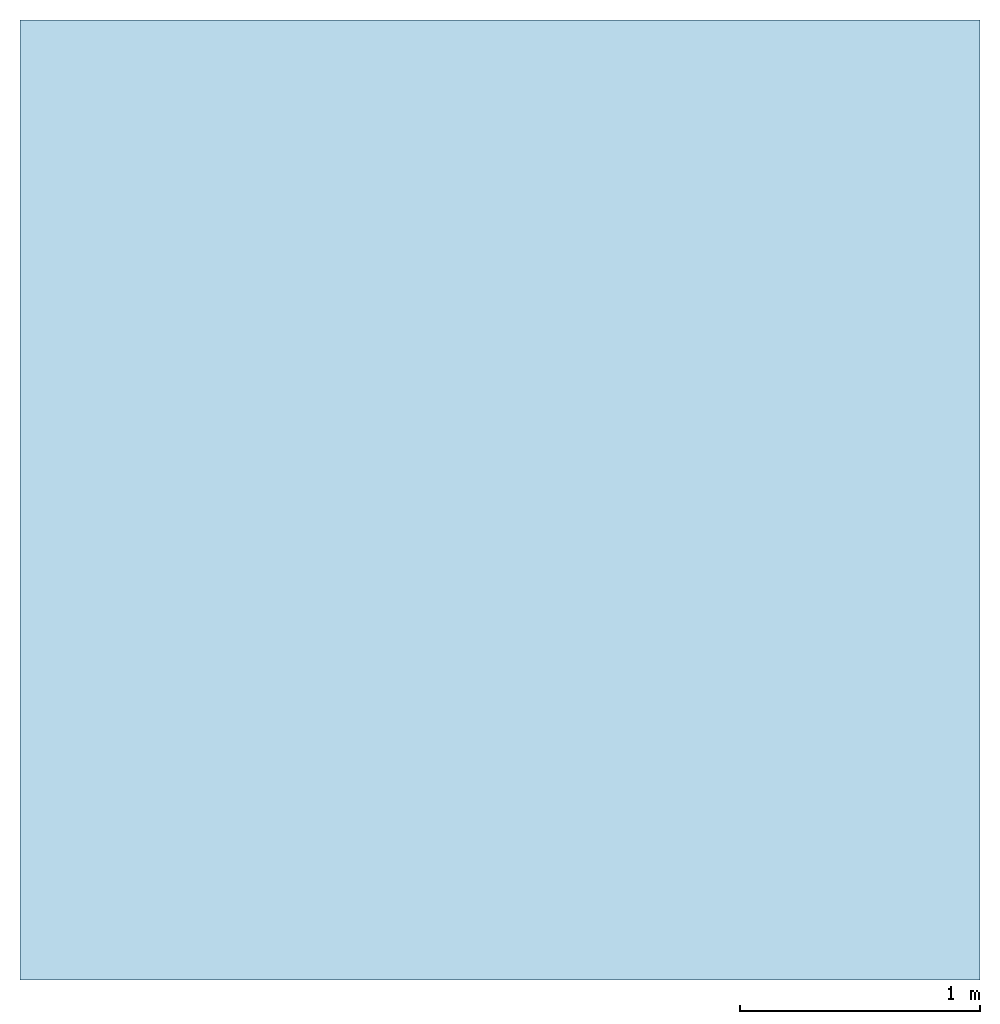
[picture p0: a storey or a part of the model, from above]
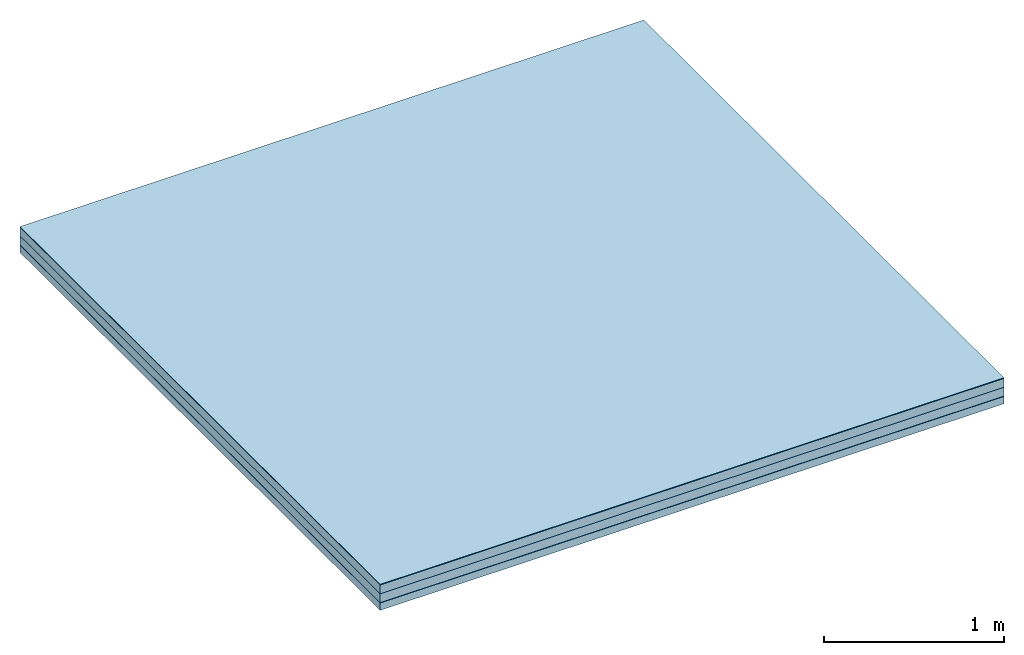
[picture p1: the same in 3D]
Properties of the parts of a building model (IFC2X3)

# File
Description: ViewDefinition [CoordinationView_V2.0]
File name: 0001
Time: 2021-03-09T11:43:43
Written by: The EXPRESS Data Manager Version 5.02.0100.07 : 28 Aug 2013
Made in: 20190108_1515(x64) - Exporter 19.2.1.1 - IU alternativa 19.2.1.1
Comment: STEP Physical File produced by: The EXPRESS Data Manager Version 5.02.0100.07 : 28 Aug 2013 * Module: EDMstepFileFactory/EDMstandAlone * Creation date: Tue Mar 09 11:43:43 2021 * Host: DESKTOP-9PSOHM7 * Database: C:\Users\MODELA~1\AppData\Local\Temp\{47D59A90-F0F7-4EF9-9812-D2957C08A82E}\ifc * Database version: 5507 * Database creation date: Tue Mar 09 11:43:42 2021 * Schema: IFC2X3 * Model: DataRepository.ifc * Model creation date: Tue Mar 09 11:43:43 2021 * Header model: DataRepository.ifc_HeaderModel * Header model creation date: Tue Mar 09 11:43:43 2021 * EDMuser: sdai-user * EDMgroup: sdai-group * License ID and type: 5605 : Permanent license. Expiry date: * EDMstepFileFactory options: 020000

# IfcProject, 0001
LongName: Nombre de proyecto; Phase: Estado de proyecto

# IfcSite, Default
RefLatitude: 40, 24, 0, 5493; RefLongitude: -3, -40, -59, -880065; RefElevation: 0 mm

# IfcBuilding
Pset_BuildingCommon - NumberOfStoreys: 1

# IfcBuildingStorey, Nivel 1
LongName: Nivel 1; Elevation: 0 mm

# IfcRoof (5)
In: Nivel 1
Pset_RoofCommon - Reference: Pieza; IsExternal: no; TotalArea: 16 m2
Name (Pieza:...) | Material
139311 | IM_LaminaAsfaltica_Lamina_PolitaberNatureCombi50GBlanco
139312 | IM_LaminaAsfaltica_Lamina_PolitaberVel30 (LBM 30-FV)
139313 | AT_LanaRocaAltaDensidad_Panel_LarocS175
141563 | AT_LanaRocaAltaDensidad_Panel_LarocN175
142139 | IM_LaminaAsfaltica_Lamina_ChovaplastAlumBV30-E2

# IfcSlab: Suelo:Chapa grecada, Suelo:Chapa grecada:142878
In: Nivel 1
PredefinedType: FLOOR; Material: Formación de pendiente - Chapa grecada 1 mm, Formación de pendiente - Chapa grecada 49 mm
Pset_SlabCommon - IsExternal: no; Reference: Chapa grecada; LoadBearing: no; ThermalTransmittance: 900 kg/K/s3; PitchAngle: 0 deg
